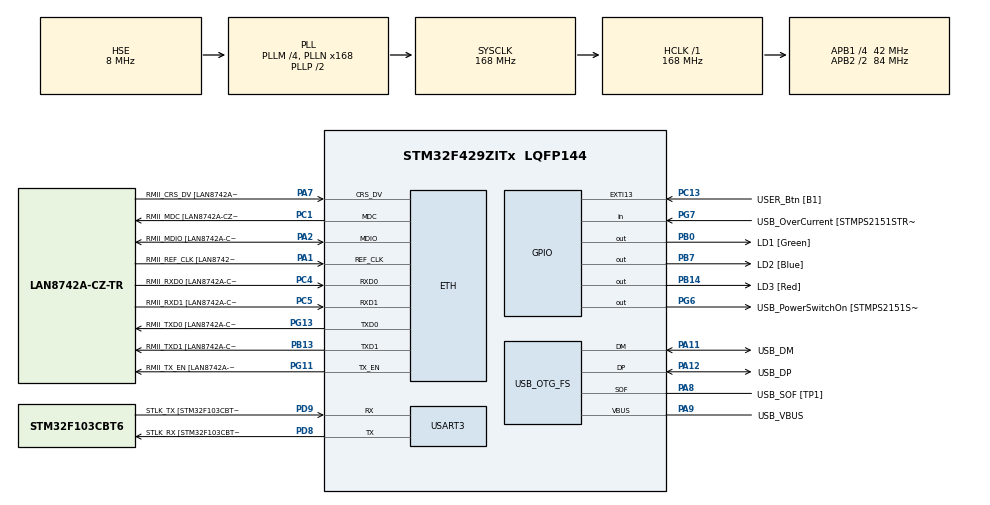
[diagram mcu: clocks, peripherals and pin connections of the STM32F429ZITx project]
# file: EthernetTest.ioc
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Mcu.Family=STM32F4
RCC.CortexFreq_Value=168000000
PG6.Signal=GPIO_Output
PB14.GPIO_Label=LD3 [Red]
PG6.GPIO_Label=USB_PowerSwitchOn [STMPS2151STR_EN]
PA14.GPIO_Label=TCK
RCC.SYSCLKSourceVirtual=RCC_SYSCLKSOURCE_PLLCLK
PA11.Mode=Device_Only
PB0.GPIO_Label=LD1 [Green]
PC14/OSC32_IN.Mode=LSE-External-Oscillator
PC5.Mode=RMII
PC13.GPIO_Label=USER_Btn [B1]
PB13.GPIO_Label=RMII_TXD1 [LAN8742A-CZ-TR_TXD1]
PB13.Signal=ETH_TXD1
PG13.Signal=ETH_TXD0
PD9.Mode=Asynchronous
PG11.Signal=ETH_TX_EN
RCC.SYSCLKSource=RCC_SYSCLKSOURCE_PLLCLK
ProjectManager.StackSize=0x400
VP_FREERTOS_VS_CMSIS_V2.Mode=CMSIS_V2
PA12.Signal=USB_OTG_FS_DP
ETH.PHY_Value=0
PH0/OSC_IN.Mode=HSE-External-Clock-Source
RCC.HCLKFreq_Value=168000000
RCC.APB2TimFreq_Value=168000000
PH1/OSC_OUT.Signal=RCC_OSC_OUT
PD8.Signal=USART3_TX
RCC.AHBFreq_Value=168000000
NVIC.ETH_IRQn=true\:5\:0\:false\:false\:true\:true\:false\:true
RCC.HSE_VALUE=8000000
RCC.PLLMUL=RCC_PLL_MUL9
PC4.GPIO_Label=RMII_RXD0 [LAN8742A-CZ-TR_RXD0]
PA14.Mode=Serial_Wire
PA10.GPIO_Label=USB_ID
PB7.Signal=GPIO_Output
PA8.Signal=USB_OTG_FS_SOF
PG13.Mode=RMII
ETH.PHY_Name=LAN8742A_PHY_ADDRESS
PH1/OSC_OUT.Mode=HSE-External-Clock-Source
PB7.GPIO_Label=LD2 [Blue]
Mcu.Package=LQFP144
PC14/OSC32_IN.Signal=RCC_OSC32_IN
PA2.GPIO_Label=RMII_MDIO [LAN8742A-CZ-TR_MDIO]
PA10.Signal=USB_OTG_FS_ID
USB_OTG_FS.VirtualMode=Device_Only
RCC.APB2CLKDivider=RCC_HCLK_DIV2
RCC.APB1TimFreq_Value=84000000
PG11.GPIO_Label=RMII_TX_EN [LAN8742A-CZ-TR_TXEN]
PC5.Signal=ETH_RXD1
PB13.Mode=RMII
PC4.Mode=RMII
FREERTOS.Tasks01=defaultTask,24,128,StartDefaultTask,Default,NULL,Dynamic,NULL,NULL
PA7.Mode=RMII
PG7.Signal=GPIO_Input
PD9.GPIO_Label=STLK_TX [STM32F103CBT6_PA2]
PC13.Signal=GPXTI13
PA9.GPIO_Label=USB_VBUS
PC4.Signal=ETH_RXD0
PA11.GPIO_Label=USB_DM
PD9.Signal=USART3_RX
RCC.APB1CLKDivider=RCC_HCLK_DIV4
PG13.GPIO_Label=RMII_TXD0 [LAN8742A-CZ-TR_TXD0]
ETH.PhyAddress=0
PA12.GPIO_Label=USB_DP
VP_LWIP_VS_Enabled.Mode=Enabled
PD8.GPIO_Label=STLK_RX [STM32F103CBT6_PA3]
PA13.Signal=SYS_JTMS-SWDIO
PA9.Mode=Activate_VBUS
PA8.GPIO_Label=USB_SOF [TP1]
ProjectManager.TargetToolchain=Makefile
PA9.Signal=USB_OTG_FS_VBUS
RCC.USBFreq_Value=48000000
PD8.Mode=Asynchronous
PA1.Signal=ETH_REF_CLK
PB14.Signal=GPIO_Output
board=NUCLEO-F429ZI
RCC.VCOOutputFreq_Value=336000000
PH0/OSC_IN.Signal=RCC_OSC_IN
RCC.APB2Freq_Value=84000000
PA1.Mode=RMII
RCC.PRESCALERUSB=RCC_USBCLKSOURCE_PLL_DIV1_5
PG7.GPIO_Label=USB_OverCurrent [STMPS2151STR_FAULT]
PA1.GPIO_Label=RMII_REF_CLK [LAN8742A-CZ-TR_REFCLK0]
PC1.GPIO_Label=RMII_MDC [LAN8742A-CZ-TR_MDC]
PA13.Mode=Serial_Wire
Mcu.Name=STM32F429ZITx
PA2.Signal=ETH_MDIO
PA13.GPIO_Label=TMS
RCC.APB2TimCLKDivider=2
RCC.48MHZClocksFreq_Value=48000000
RCC.SYSCLKFreq_VALUE=168000000
ETH.MediaInterface=ETH_MEDIA_INTERFACE_RMII
PA7.GPIO_Label=RMII_CRS_DV [LAN8742A-CZ-TR_CRS_DV]
PA12.Mode=Device_Only
PC5.GPIO_Label=RMII_RXD1 [LAN8742A-CZ-TR_RXD1]
USART3.VirtualMode=VM_ASYNC
PC15/OSC32_OUT.Mode=LSE-External-Oscillator
PG11.Mode=RMII
PA11.Signal=USB_OTG_FS_DM
PA14.Signal=SYS_JTCK-SWCLK
ProjectManager.HeapSize=0x200
LWIP.Version=v2.1.2_Cube
RCC.HSI_VALUE=16000000
PH0/OSC_IN.GPIO_Label=MCO [STM32F103CBT6_PA8]
RCC.PLLQ=7
NVIC.PriorityGroup=NVIC_PRIORITYGROUP_4
RCC.PLLM=4
RCC.PLLN=168
PA2.Mode=RMII
PC15/OSC32_OUT.Signal=RCC_OSC32_OUT
PA8.Mode=Activate_SOF_FS
RCC.APB1Freq_Value=42000000
PB0.Signal=GPIO_Output
PC1.Signal=ETH_MDC
PC1.Mode=RMII
PA7.Signal=ETH_CRS_DV

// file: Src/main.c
/* USER CODE BEGIN Header */
/**
  ******************************************************************************
  * @file           : main.c
  * @brief          : Main program body
  ******************************************************************************
  * @attention
  *
  * <h2><center>&copy; Copyright (c) 2021 STMicroelectronics.
  * All rights reserved.</center></h2>
  *
  * This software component is licensed by ST under Ultimate Liberty license
  * SLA0044, the "License"; You may not use this file except in compliance with
  * the License. You may obtain a copy of the License at:
  *                             www.st.com/SLA0044
  *
  ******************************************************************************
  */
/* USER CODE END Header */

#include "main.h"
#include "cmsis_os.h"
#include "lwip.h"
#include "sockets.h"

UART_HandleTypeDef huart3;

PCD_HandleTypeDef hpcd_USB_OTG_FS;

/* Definitions for defaultTask */
osThreadId_t defaultTaskHandle;
const osThreadAttr_t defaultTask_attributes = {
  .name = "defaultTask",
  .priority = (osPriority_t) osPriorityNormal,
  .stack_size = 128 * 4
};

void SystemClock_Config(void);
static void MX_GPIO_Init(void);
static void MX_USART3_UART_Init(void);
static void MX_USB_OTG_FS_PCD_Init(void);
void StartDefaultTask(void *argument);

int main(void)
{

  /* MCU Configuration--------------------------------------------------------*/

  // Testing the crystal: TODO remove these lines
  RCC->CR |= RCC_CR_HSEON;
	while(!(RCC->CR & RCC_CR_HSERDY))
		__ISB();
	__DSB(); // set breakpoint here, is it reached?

  /* Reset of all peripherals, Initializes the Flash interface and the Systick. */
  HAL_Init();

  /* Configure the system clock */
  SystemClock_Config();

  /* Initialize all configured peripherals */
  MX_GPIO_Init();
  MX_USART3_UART_Init();
  // MX_USB_OTG_FS_PCD_Init();
  /* USER CODE BEGIN 2 */

  // For testing: attempt to repeatedly message UART
  // Before the OS is initialized.
  // char *data = "Hello from main!\n";
  // while(1) {
  //   // Toggle an LED
  //   HAL_GPIO_WritePin(GPIOE, GPIO_PIN_12, GPIO_PIN_SET);
  //   HAL_Delay(1000);
  //   HAL_GPIO_WritePin(GPIOE, GPIO_PIN_12, GPIO_PIN_RESET);
  //   HAL_Delay(1000);
  //   HAL_UART_Transmit(&huart3, data, strlen(data), 50);
  // }

  /* USER CODE END 2 */

  /* Init scheduler */
  osKernelInitialize();

  /* Create the thread(s) */
  /* creation of defaultTask */
  defaultTaskHandle = osThreadNew(StartDefaultTask, NULL, &defaultTask_attributes);

  /* Start scheduler */
  osKernelStart();

  /* We should never get here as control is now taken by the scheduler */
  /* Infinite loop */
  while (1)
  {

  }
}

void SystemClock_Config(void)
{
  RCC_OscInitTypeDef RCC_OscInitStruct = {0};
  RCC_ClkInitTypeDef RCC_ClkInitStruct = {0};

  /** Configure the main internal regulator output voltage
  */
  __HAL_RCC_PWR_CLK_ENABLE();
  __HAL_PWR_VOLTAGESCALING_CONFIG(PWR_REGULATOR_VOLTAGE_SCALE1);
  /** Initializes the CPU, AHB and APB busses clocks
  */
  RCC_OscInitStruct.OscillatorType = RCC_OSCILLATORTYPE_HSE;
  RCC_OscInitStruct.HSEState = RCC_HSE_BYPASS;
  RCC_OscInitStruct.PLL.PLLState = RCC_PLL_ON;
  RCC_OscInitStruct.PLL.PLLSource = RCC_PLLSOURCE_HSE;
  RCC_OscInitStruct.PLL.PLLM = 4;
  RCC_OscInitStruct.PLL.PLLN = 168;
  RCC_OscInitStruct.PLL.PLLP = RCC_PLLP_DIV2;
  RCC_OscInitStruct.PLL.PLLQ = 7;
  if (HAL_RCC_OscConfig(&RCC_OscInitStruct) != HAL_OK)
  {
    Error_Handler();
  }
  /** Initializes the CPU, AHB and APB busses clocks
  */
  RCC_ClkInitStruct.ClockType = RCC_CLOCKTYPE_HCLK|RCC_CLOCKTYPE_SYSCLK
                              |RCC_CLOCKTYPE_PCLK1|RCC_CLOCKTYPE_PCLK2;
  RCC_ClkInitStruct.SYSCLKSource = RCC_SYSCLKSOURCE_PLLCLK;
  RCC_ClkInitStruct.AHBCLKDivider = RCC_SYSCLK_DIV1;
  RCC_ClkInitStruct.APB1CLKDivider = RCC_HCLK_DIV4;
  RCC_ClkInitStruct.APB2CLKDivider = RCC_HCLK_DIV2;

  if (HAL_RCC_ClockConfig(&RCC_ClkInitStruct, FLASH_LATENCY_5) != HAL_OK)
  {
    Error_Handler();
  }
}

static void MX_USART3_UART_Init(void)
{

  huart3.Instance = USART3;
  huart3.Init.BaudRate = 115200;
  huart3.Init.WordLength = UART_WORDLENGTH_8B;
  huart3.Init.StopBits = UART_STOPBITS_1;
  huart3.Init.Parity = UART_PARITY_NONE;
  huart3.Init.Mode = UART_MODE_TX_RX;
  huart3.Init.HwFlowCtl = UART_HWCONTROL_NONE;
  huart3.Init.OverSampling = UART_OVERSAMPLING_16;
  if (HAL_UART_Init(&huart3) != HAL_OK)
  {
    Error_Handler();
  }

}

static void MX_USB_OTG_FS_PCD_Init(void)
{

  hpcd_USB_OTG_FS.Instance = USB_OTG_FS;
  hpcd_USB_OTG_FS.Init.dev_endpoints = 4;
  hpcd_USB_OTG_FS.Init.speed = PCD_SPEED_FULL;
  hpcd_USB_OTG_FS.Init.dma_enable = DISABLE;
  hpcd_USB_OTG_FS.Init.phy_itface = PCD_PHY_EMBEDDED;
  hpcd_USB_OTG_FS.Init.Sof_enable = ENABLE;
  hpcd_USB_OTG_FS.Init.low_power_enable = DISABLE;
  hpcd_USB_OTG_FS.Init.lpm_enable = DISABLE;
  hpcd_USB_OTG_FS.Init.vbus_sensing_enable = ENABLE;
  hpcd_USB_OTG_FS.Init.use_dedicated_ep1 = DISABLE;
  if (HAL_PCD_Init(&hpcd_USB_OTG_FS) != HAL_OK)
  {
    Error_Handler();
  }

}

static void MX_GPIO_Init(void)
{
  GPIO_InitTypeDef GPIO_InitStruct = {0};

  /* GPIO Ports Clock Enable */
  __HAL_RCC_GPIOC_CLK_ENABLE();
  __HAL_RCC_GPIOH_CLK_ENABLE();
  __HAL_RCC_GPIOA_CLK_ENABLE();
  __HAL_RCC_GPIOB_CLK_ENABLE();
  __HAL_RCC_GPIOD_CLK_ENABLE();
  __HAL_RCC_GPIOG_CLK_ENABLE();

  // /*Configure GPIO pin Output Level */
  // HAL_GPIO_WritePin(GPIOB, LD1_Pin|LD3_Pin|LD2_Pin, GPIO_PIN_RESET);

  // /*Configure GPIO pin Output Level */
  // HAL_GPIO_WritePin(USB_PowerSwitchOn_GPIO_Port, USB_PowerSwitchOn_Pin, GPIO_PIN_RESET);

  // /*Configure GPIO pin : USER_Btn_Pin */
  // GPIO_InitStruct.Pin = USER_Btn_Pin;
  // GPIO_InitStruct.Mode = GPIO_MODE_IT_RISING;
  // GPIO_InitStruct.Pull = GPIO_NOPULL;
  // HAL_GPIO_Init(USER_Btn_GPIO_Port, &GPIO_InitStruct);

  // /*Configure GPIO pins : LD1_Pin LD3_Pin LD2_Pin */
  // GPIO_InitStruct.Pin = LD1_Pin|LD3_Pin|LD2_Pin;
  // GPIO_InitStruct.Mode = GPIO_MODE_OUTPUT_PP;
  // GPIO_InitStruct.Pull = GPIO_NOPULL;
  // GPIO_InitStruct.Speed = GPIO_SPEED_FREQ_LOW;
  // HAL_GPIO_Init(GPIOB, &GPIO_InitStruct);

  // /*Configure GPIO pin : USB_PowerSwitchOn_Pin */
  // GPIO_InitStruct.Pin = USB_PowerSwitchOn_Pin;
  // GPIO_InitStruct.Mode = GPIO_MODE_OUTPUT_PP;
  // GPIO_InitStruct.Pull = GPIO_NOPULL;
  // GPIO_InitStruct.Speed = GPIO_SPEED_FREQ_LOW;
  // HAL_GPIO_Init(USB_PowerSwitchOn_GPIO_Port, &GPIO_InitStruct);

  // /*Configure GPIO pin : USB_OverCurrent_Pin */
  // GPIO_InitStruct.Pin = USB_OverCurrent_Pin;
  // GPIO_InitStruct.Mode = GPIO_MODE_INPUT;
  // GPIO_InitStruct.Pull = GPIO_NOPULL;
  // HAL_GPIO_Init(USB_OverCurrent_GPIO_Port, &GPIO_InitStruct);

  // Initialize some LEDs
  __HAL_RCC_GPIOE_CLK_ENABLE();
  GPIO_InitStruct.Pin = GPIO_PIN_13 | GPIO_PIN_12 | GPIO_PIN_11 | GPIO_PIN_10 | GPIO_PIN_9 | GPIO_PIN_8;
  GPIO_InitStruct.Mode = GPIO_MODE_OUTPUT_PP;
  GPIO_InitStruct.Pull = GPIO_NOPULL;
  GPIO_InitStruct.Speed = GPIO_SPEED_LOW;
  HAL_GPIO_Init(GPIOE, &GPIO_InitStruct);
}

void StartDefaultTask(void *argument)
{
  struct sockaddr_in sLocalAddr;

  char *data = "Checkpoint 1\n";
  HAL_UART_Transmit(&huart3, data, strlen(data), 50);

  /* init code for LWIP */
  MX_LWIP_Init();

  /* USER CODE BEGIN 5 */
  int lSocket = lwip_socket(AF_INET, SOCK_STREAM, 0);

  data = "Checkpoint 2\n";
  HAL_UART_Transmit(&huart3, data, strlen(data), 50);

  // TODO: replace all the returns in this function with some error handling.
  if(lSocket < 0) return;

  memset((char*)&sLocalAddr, 0, sizeof(sLocalAddr));
  sLocalAddr.sin_family = AF_INET;
  sLocalAddr.sin_len    = sizeof(sLocalAddr);
  sLocalAddr.sin_addr.s_addr = htonl(INADDR_ANY);
  sLocalAddr.sin_port   = htons(23);

  if(lwip_bind(lSocket, (struct sockaddr*)&sLocalAddr, sizeof(sLocalAddr)) < 0) {
    lwip_close(lSocket);
    return;
  }

  data = "Checkpoint 3\n";
  HAL_UART_Transmit(&huart3, data, strlen(data), 50);

  if(lwip_listen(lSocket, 20) != 0) {
    lwip_close(lSocket);
    return;
  }

  /* Infinite loop */
  while(1)
  {
    int clientfd;
    struct sockaddr_in client_addr;
    int addrlen = sizeof(client_addr);
    char buffer[1024];
    int nbytes;

    data = "Checkpoint 4\n";
    HAL_UART_Transmit(&huart3, data, strlen(data), 50);

    clientfd = lwip_accept(lSocket, (struct sockaddr*)&client_addr, (socklen_t*)&addrlen);
    if(clientfd > 0) {
      do {
        nbytes = lwip_recv(clientfd, buffer, sizeof(buffer), 0);
        if(nbytes > 0)  {
          lwip_send(clientfd, buffer, nbytes, 0);
        }
      } while(nbytes > 0);
    }
  }

  lwip_close(lSocket);
  /* USER CODE END 5 */
}

void Error_Handler(void)
{
  /* USER CODE BEGIN Error_Handler_Debug */
  /* User can add his own implementation to report the HAL error return state */
  while(1); // Spin to preserve stack for debugging
  /* USER CODE END Error_Handler_Debug */
}

/************************ (C) COPYRIGHT STMicroelectronics *****END OF FILE****/
